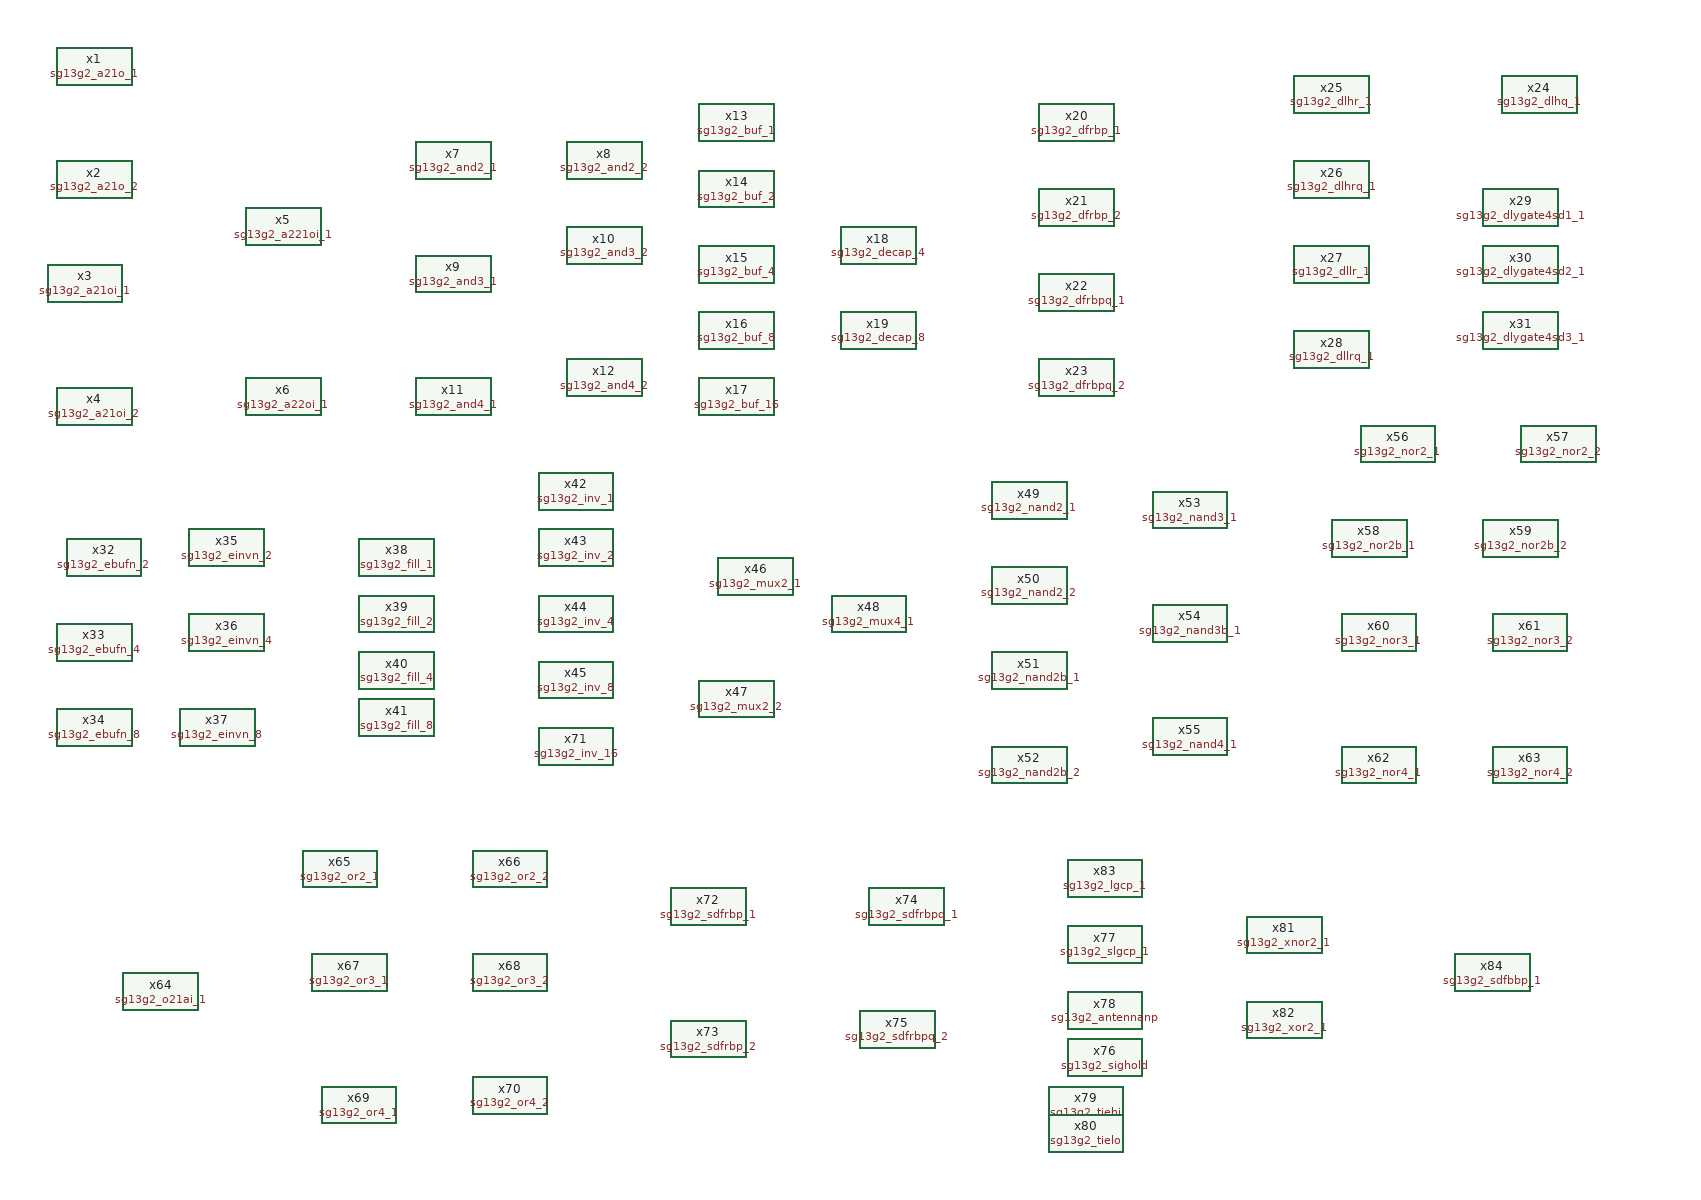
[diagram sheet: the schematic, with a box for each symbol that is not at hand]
v {xschem version=3.4.8RC file_version=1.3}
G {}
K {}
V {}
S {}
F {}
E {}
C {devices/title.sym} -90 0 0 0 {name=l1 author="IHP PDK Authors"}
C {sg13g2_a21o_1.sym} -550 -1300 0 0 {name=x1 VDD=VDD VSS=VSS prefix=sg13g2_ }
C {sg13g2_a21o_2.sym} -550 -1180 0 0 {name=x2 VDD=VDD VSS=VSS prefix=sg13g2_ }
C {sg13g2_a21oi_1.sym} -560 -1070 0 0 {name=x3 VDD=VDD VSS=VSS prefix=sg13g2_ }
C {sg13g2_a21oi_2.sym} -550 -940 0 0 {name=x4 VDD=VDD VSS=VSS prefix=sg13g2_ }
C {sg13g2_a221oi_1.sym} -350 -1130 0 0 {name=x5 VDD=VDD VSS=VSS prefix=sg13g2_ }
C {sg13g2_a22oi_1.sym} -350 -950 0 0 {name=x6 VDD=VDD VSS=VSS prefix=sg13g2_ }
C {sg13g2_and2_1.sym} -170 -1200 0 0 {name=x7 VDD=VDD VSS=VSS prefix=sg13g2_ }
C {sg13g2_and2_2.sym} -10 -1200 0 0 {name=x8 VDD=VDD VSS=VSS prefix=sg13g2_ }
C {sg13g2_and3_1.sym} -170 -1080 0 0 {name=x9 VDD=VDD VSS=VSS prefix=sg13g2_ }
C {sg13g2_and3_2.sym} -10 -1110 0 0 {name=x10 VDD=VDD VSS=VSS prefix=sg13g2_ }
C {sg13g2_and4_1.sym} -170 -950 0 0 {name=x11 VDD=VDD VSS=VSS prefix=sg13g2_ }
C {sg13g2_and4_2.sym} -10 -970 0 0 {name=x12 VDD=VDD VSS=VSS prefix=sg13g2_ }
C {sg13g2_buf_1.sym} 130 -1240 0 0 {name=x13 VDD=VDD VSS=VSS prefix=sg13g2_ }
C {sg13g2_buf_2.sym} 130 -1170 0 0 {name=x14 VDD=VDD VSS=VSS prefix=sg13g2_ }
C {sg13g2_buf_4.sym} 130 -1090 0 0 {name=x15 VDD=VDD VSS=VSS prefix=sg13g2_ }
C {sg13g2_buf_8.sym} 130 -1020 0 0 {name=x16 VDD=VDD VSS=VSS prefix=sg13g2_ }
C {sg13g2_buf_16.sym} 130 -950 0 0 {name=x17 VDD=VDD VSS=VSS prefix=sg13g2_ }
C {sg13g2_decap_4.sym} 280 -1110 0 0 {name=x18 VDD=VDD VSS=VSS prefix=sg13g2_ }
C {sg13g2_decap_8.sym} 280 -1020 0 0 {name=x19 VDD=VDD VSS=VSS prefix=sg13g2_ }
C {sg13g2_dfrbp_1.sym} 490 -1240 0 0 {name=x20 VDD=VDD VSS=VSS prefix=sg13g2_ }
C {sg13g2_dfrbp_2.sym} 490 -1150 0 0 {name=x21 VDD=VDD VSS=VSS prefix=sg13g2_ }
C {sg13g2_dfrbpq_1.sym} 490 -1060 0 0 {name=x22 VDD=VDD VSS=VSS prefix=sg13g2_ }
C {sg13g2_dfrbpq_2.sym} 490 -970 0 0 {name=x23 VDD=VDD VSS=VSS prefix=sg13g2_ }
C {sg13g2_dlhq_1.sym} 980 -1270 0 0 {name=x24 VDD=VDD VSS=VSS prefix=sg13g2_ }
C {sg13g2_dlhr_1.sym} 760 -1270 0 0 {name=x25 VDD=VDD VSS=VSS prefix=sg13g2_ }
C {sg13g2_dlhrq_1.sym} 760 -1180 0 0 {name=x26 VDD=VDD VSS=VSS prefix=sg13g2_ }
C {sg13g2_dllr_1.sym} 760 -1090 0 0 {name=x27 VDD=VDD VSS=VSS prefix=sg13g2_ }
C {sg13g2_dllrq_1.sym} 760 -1000 0 0 {name=x28 VDD=VDD VSS=VSS prefix=sg13g2_ }
C {sg13g2_dlygate4sd1_1.sym} 960 -1150 0 0 {name=x29 VDD=VDD VSS=VSS prefix=sg13g2_ }
C {sg13g2_dlygate4sd2_1.sym} 960 -1090 0 0 {name=x30 VDD=VDD VSS=VSS prefix=sg13g2_ }
C {sg13g2_dlygate4sd3_1.sym} 960 -1020 0 0 {name=x31 VDD=VDD VSS=VSS prefix=sg13g2_ }
C {sg13g2_ebufn_2.sym} -540 -780 0 0 {name=x32 VDD=VDD VSS=VSS prefix=sg13g2_ }
C {sg13g2_ebufn_4.sym} -550 -690 0 0 {name=x33 VDD=VDD VSS=VSS prefix=sg13g2_ }
C {sg13g2_ebufn_8.sym} -550 -600 0 0 {name=x34 VDD=VDD VSS=VSS prefix=sg13g2_ }
C {sg13g2_einvn_2.sym} -410 -790 0 0 {name=x35 VDD=VDD VSS=VSS prefix=sg13g2_ }
C {sg13g2_einvn_4.sym} -410 -700 0 0 {name=x36 VDD=VDD VSS=VSS prefix=sg13g2_ }
C {sg13g2_einvn_8.sym} -420 -600 0 0 {name=x37 VDD=VDD VSS=VSS prefix=sg13g2_ }
C {sg13g2_fill_1.sym} -230 -780 0 0 {name=x38 VDD=VDD VSS=VSS prefix=sg13g2_ }
C {sg13g2_fill_2.sym} -230 -720 0 0 {name=x39 VDD=VDD VSS=VSS prefix=sg13g2_ }
C {sg13g2_fill_4.sym} -230 -660 0 0 {name=x40 VDD=VDD VSS=VSS prefix=sg13g2_ }
C {sg13g2_fill_8.sym} -230 -610 0 0 {name=x41 VDD=VDD VSS=VSS prefix=sg13g2_ }
C {sg13g2_inv_1.sym} -40 -850 0 0 {name=x42 VDD=VDD VSS=VSS prefix=sg13g2_ }
C {sg13g2_inv_2.sym} -40 -790 0 0 {name=x43 VDD=VDD VSS=VSS prefix=sg13g2_ }
C {sg13g2_inv_4.sym} -40 -720 0 0 {name=x44 VDD=VDD VSS=VSS prefix=sg13g2_ }
C {sg13g2_inv_8.sym} -40 -650 0 0 {name=x45 VDD=VDD VSS=VSS prefix=sg13g2_ }
C {sg13g2_mux2_1.sym} 150 -760 0 0 {name=x46 VDD=VDD VSS=VSS prefix=sg13g2_ }
C {sg13g2_mux2_2.sym} 130 -630 0 0 {name=x47 VDD=VDD VSS=VSS prefix=sg13g2_ }
C {sg13g2_mux4_1.sym} 270 -720 0 0 {name=x48 VDD=VDD VSS=VSS prefix=sg13g2_ }
C {sg13g2_nand2_1.sym} 440 -840 0 0 {name=x49 VDD=VDD VSS=VSS prefix=sg13g2_ }
C {sg13g2_nand2_2.sym} 440 -750 0 0 {name=x50 VDD=VDD VSS=VSS prefix=sg13g2_ }
C {sg13g2_nand2b_1.sym} 440 -660 0 0 {name=x51 VDD=VDD VSS=VSS prefix=sg13g2_ }
C {sg13g2_nand2b_2.sym} 440 -560 0 0 {name=x52 VDD=VDD VSS=VSS prefix=sg13g2_ }
C {sg13g2_nand3_1.sym} 610 -830 0 0 {name=x53 VDD=VDD VSS=VSS prefix=sg13g2_ }
C {sg13g2_nand3b_1.sym} 610 -710 0 0 {name=x54 VDD=VDD VSS=VSS prefix=sg13g2_ }
C {sg13g2_nand4_1.sym} 610 -590 0 0 {name=x55 VDD=VDD VSS=VSS prefix=sg13g2_ }
C {sg13g2_nor2_1.sym} 830 -900 0 0 {name=x56 VDD=VDD VSS=VSS prefix=sg13g2_ }
C {sg13g2_nor2_2.sym} 1000 -900 0 0 {name=x57 VDD=VDD VSS=VSS prefix=sg13g2_ }
C {sg13g2_nor2b_1.sym} 800 -800 0 0 {name=x58 VDD=VDD VSS=VSS prefix=sg13g2_ }
C {sg13g2_nor2b_2.sym} 960 -800 0 0 {name=x59 VDD=VDD VSS=VSS prefix=sg13g2_ }
C {sg13g2_nor3_1.sym} 810 -700 0 0 {name=x60 VDD=VDD VSS=VSS prefix=sg13g2_ }
C {sg13g2_nor3_2.sym} 970 -700 0 0 {name=x61 VDD=VDD VSS=VSS prefix=sg13g2_ }
C {sg13g2_nor4_1.sym} 810 -560 0 0 {name=x62 VDD=VDD VSS=VSS prefix=sg13g2_ }
C {sg13g2_nor4_2.sym} 970 -560 0 0 {name=x63 VDD=VDD VSS=VSS prefix=sg13g2_ }
C {sg13g2_o21ai_1.sym} -480 -320 0 0 {name=x64 VDD=VDD VSS=VSS prefix=sg13g2_ }
C {sg13g2_or2_1.sym} -290 -450 0 0 {name=x65 VDD=VDD VSS=VSS prefix=sg13g2_ }
C {sg13g2_or2_2.sym} -110 -450 0 0 {name=x66 VDD=VDD VSS=VSS prefix=sg13g2_ }
C {sg13g2_or3_1.sym} -280 -340 0 0 {name=x67 VDD=VDD VSS=VSS prefix=sg13g2_ }
C {sg13g2_or3_2.sym} -110 -340 0 0 {name=x68 VDD=VDD VSS=VSS prefix=sg13g2_ }
C {sg13g2_or4_1.sym} -270 -200 0 0 {name=x69 VDD=VDD VSS=VSS prefix=sg13g2_ }
C {sg13g2_or4_2.sym} -110 -210 0 0 {name=x70 VDD=VDD VSS=VSS prefix=sg13g2_ }
C {sg13g2_sdfrbp_1.sym} 100 -410 0 0 {name=x72 VDD=VDD VSS=VSS prefix=sg13g2_ }
C {sg13g2_sdfrbp_2.sym} 100 -270 0 0 {name=x73 VDD=VDD VSS=VSS prefix=sg13g2_ }
C {sg13g2_sdfrbpq_1.sym} 310 -410 0 0 {name=x74 VDD=VDD VSS=VSS prefix=sg13g2_ }
C {sg13g2_sdfrbpq_2.sym} 300 -280 0 0 {name=x75 VDD=VDD VSS=VSS prefix=sg13g2_ }
C {sg13g2_sighold.sym} 520 -250 0 0 {name=x76 VDD=VDD VSS=VSS prefix=sg13g2_ }
C {sg13g2_slgcp_1.sym} 520 -370 0 0 {name=x77 VDD=VDD VSS=VSS prefix=sg13g2_ }
C {sg13g2_antennanp.sym} 520 -300 0 0 {name=x78 VDD=VDD VSS=VSS prefix=sg13g2_ }
C {sg13g2_tiehi.sym} 500 -200 0 0 {name=x79 VDD=VDD VSS=VSS prefix=sg13g2_ }
C {sg13g2_tielo.sym} 500 -170 0 0 {name=x80 VDD=VDD VSS=VSS prefix=sg13g2_ }
C {sg13g2_xnor2_1.sym} 710 -380 0 0 {name=x81 VDD=VDD VSS=VSS prefix=sg13g2_ }
C {sg13g2_xor2_1.sym} 710 -290 0 0 {name=x82 VDD=VDD VSS=VSS prefix=sg13g2_ }
C {sg13g2_lgcp_1.sym} 520 -440 0 0 {name=x83 VDD=VDD VSS=VSS prefix=sg13g2_ }
C {sg13g2_inv_16.sym} -40 -580 0 0 {name=x71 VDD=VDD VSS=VSS prefix=sg13g2_ }
C {sg13g2_sdfbbp_1.sym} 930 -340 0 0 {name=x84 VDD=VDD VSS=VSS prefix=sg13g2_ }
